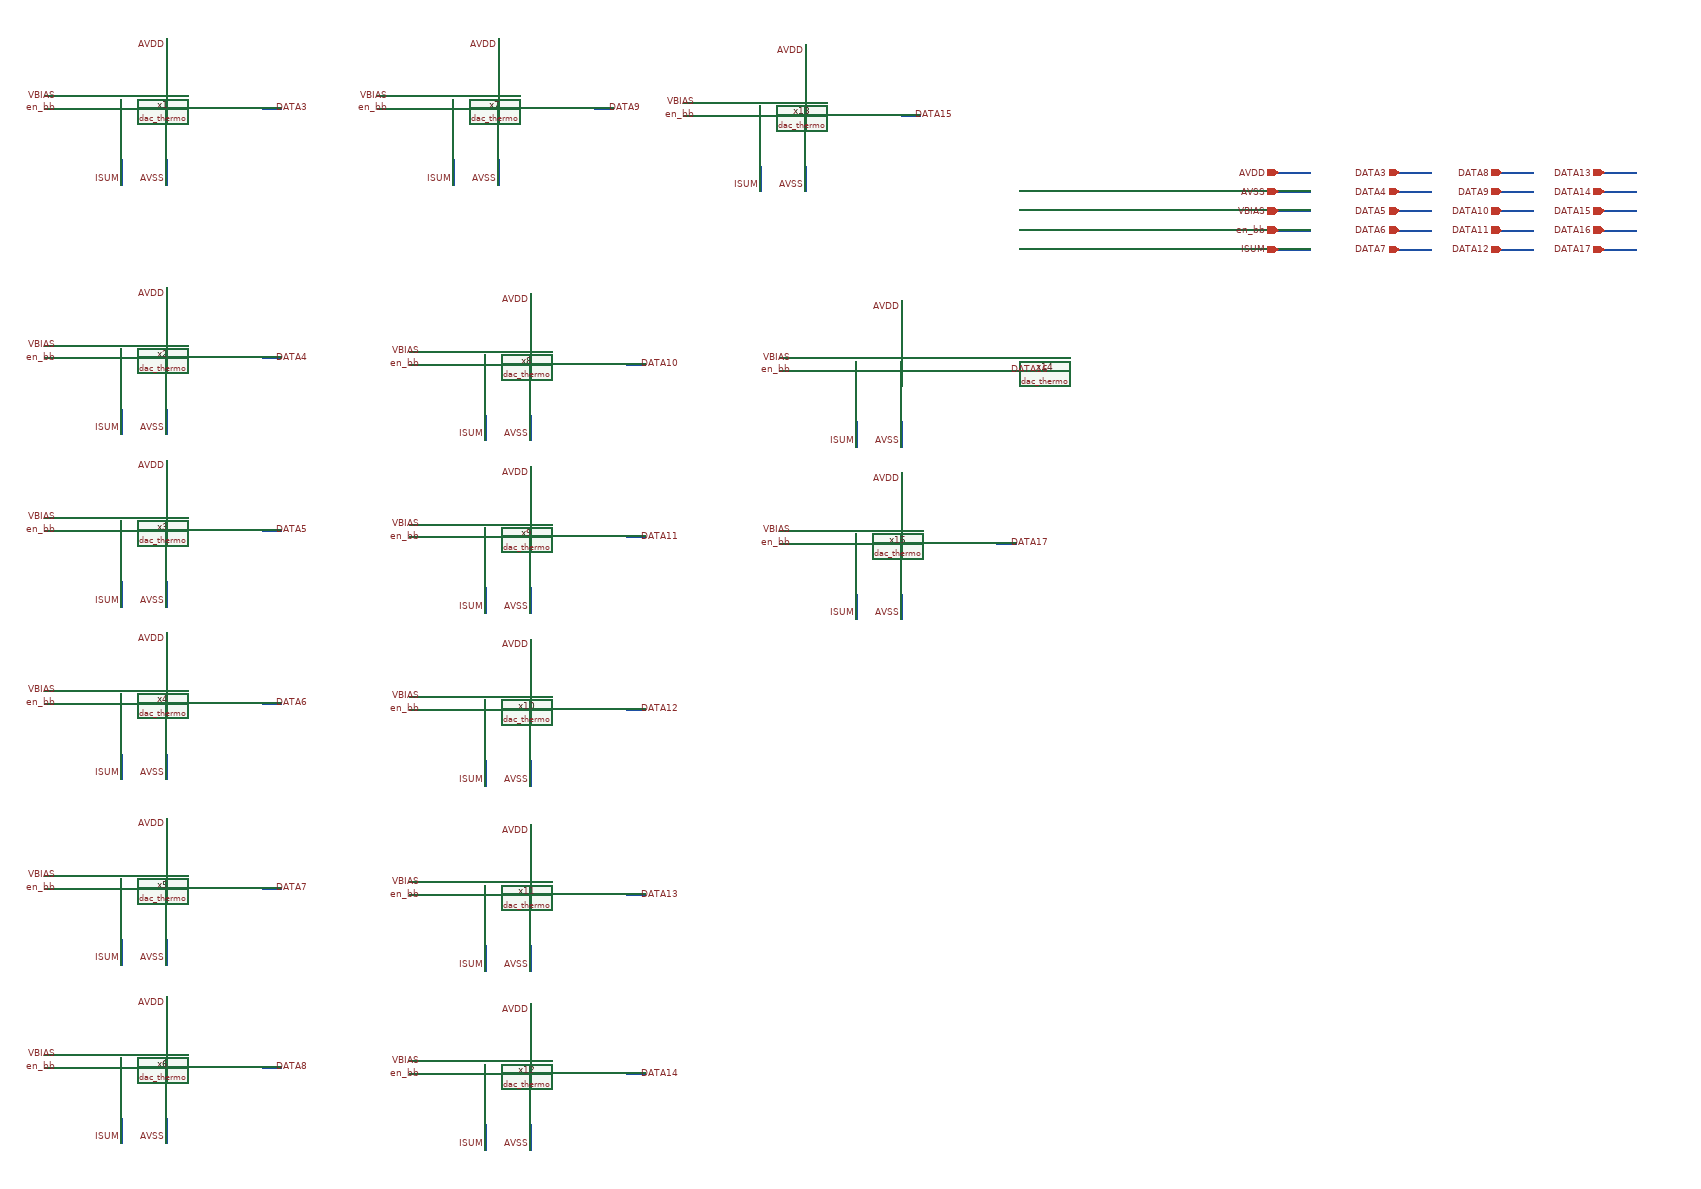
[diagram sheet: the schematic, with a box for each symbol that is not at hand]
v {xschem version=3.4.8RC file_version=1.3}
G {}
K {}
V {}
S {}
F {}
E {}
N 240 -1890 240 -1860 {lab=AVDD}
N 240 -1700 240 -1660 {lab=AVSS}
N 170 -1700 170 -1660 {lab=ISUM}
N 50 -1780 90 -1780 {lab=en_bb}
N 50 -1800 90 -1800 {lab=VBIAS}
N 390 -1780 420 -1780 {lab=DATA3}
N 240 -1500 240 -1470 {lab=AVDD}
N 240 -1310 240 -1270 {lab=AVSS}
N 170 -1310 170 -1270 {lab=ISUM}
N 50 -1390 90 -1390 {lab=en_bb}
N 50 -1410 90 -1410 {lab=VBIAS}
N 390 -1390 420 -1390 {lab=DATA4}
N 240 -1230 240 -1200 {lab=AVDD}
N 240 -1040 240 -1000 {lab=AVSS}
N 170 -1040 170 -1000 {lab=ISUM}
N 50 -1120 90 -1120 {lab=en_bb}
N 50 -1140 90 -1140 {lab=VBIAS}
N 390 -1120 420 -1120 {lab=DATA5}
N 240 -960 240 -930 {lab=AVDD}
N 240 -770 240 -730 {lab=AVSS}
N 170 -770 170 -730 {lab=ISUM}
N 50 -850 90 -850 {lab=en_bb}
N 50 -870 90 -870 {lab=VBIAS}
N 390 -850 420 -850 {lab=DATA6}
N 240 -670 240 -640 {lab=AVDD}
N 240 -480 240 -440 {lab=AVSS}
N 170 -480 170 -440 {lab=ISUM}
N 50 -560 90 -560 {lab=en_bb}
N 50 -580 90 -580 {lab=VBIAS}
N 390 -560 420 -560 {lab=DATA7}
N 240 -390 240 -360 {lab=AVDD}
N 240 -200 240 -160 {lab=AVSS}
N 170 -200 170 -160 {lab=ISUM}
N 50 -280 90 -280 {lab=en_bb}
N 50 -300 90 -300 {lab=VBIAS}
N 390 -280 420 -280 {lab=DATA8}
N 760 -1890 760 -1860 {lab=AVDD}
N 760 -1700 760 -1660 {lab=AVSS}
N 690 -1700 690 -1660 {lab=ISUM}
N 570 -1780 610 -1780 {lab=en_bb}
N 570 -1800 610 -1800 {lab=VBIAS}
N 910 -1780 940 -1780 {lab=DATA9}
N 810 -1490 810 -1460 {lab=AVDD}
N 810 -1300 810 -1260 {lab=AVSS}
N 740 -1300 740 -1260 {lab=ISUM}
N 620 -1380 660 -1380 {lab=en_bb}
N 620 -1400 660 -1400 {lab=VBIAS}
N 960 -1380 990 -1380 {lab=DATA10}
N 810 -1220 810 -1190 {lab=AVDD}
N 810 -1030 810 -990 {lab=AVSS}
N 740 -1030 740 -990 {lab=ISUM}
N 620 -1110 660 -1110 {lab=en_bb}
N 620 -1130 660 -1130 {lab=VBIAS}
N 960 -1110 990 -1110 {lab=DATA11}
N 810 -950 810 -920 {lab=AVDD}
N 810 -760 810 -720 {lab=AVSS}
N 740 -760 740 -720 {lab=ISUM}
N 620 -840 660 -840 {lab=en_bb}
N 620 -860 660 -860 {lab=VBIAS}
N 960 -840 990 -840 {lab=DATA12}
N 810 -660 810 -630 {lab=AVDD}
N 810 -470 810 -430 {lab=AVSS}
N 740 -470 740 -430 {lab=ISUM}
N 620 -550 660 -550 {lab=en_bb}
N 620 -570 660 -570 {lab=VBIAS}
N 960 -550 990 -550 {lab=DATA13}
N 810 -380 810 -350 {lab=AVDD}
N 810 -190 810 -150 {lab=AVSS}
N 740 -190 740 -150 {lab=ISUM}
N 620 -270 660 -270 {lab=en_bb}
N 620 -290 660 -290 {lab=VBIAS}
N 960 -270 990 -270 {lab=DATA14}
N 1240 -1880 1240 -1850 {lab=AVDD}
N 1240 -1690 1240 -1650 {lab=AVSS}
N 1170 -1690 1170 -1650 {lab=ISUM}
N 1050 -1770 1090 -1770 {lab=en_bb}
N 1050 -1790 1090 -1790 {lab=VBIAS}
N 1390 -1770 1420 -1770 {lab=DATA15}
N 1390 -1480 1390 -1450 {lab=AVDD}
N 1390 -1290 1390 -1250 {lab=AVSS}
N 1320 -1290 1320 -1250 {lab=ISUM}
N 1200 -1370 1240 -1370 {lab=en_bb}
N 1200 -1390 1240 -1390 {lab=VBIAS}
N 1540 -1370 1570 -1370 {lab=DATA16}
N 1390 -1210 1390 -1180 {lab=AVDD}
N 1390 -1020 1390 -980 {lab=AVSS}
N 1320 -1020 1320 -980 {lab=ISUM}
N 1200 -1100 1240 -1100 {lab=en_bb}
N 1200 -1120 1240 -1120 {lab=VBIAS}
N 1540 -1100 1570 -1100 {lab=DATA17}
N 1980 -1680 2030 -1680 {lab=AVDD}
N 1980 -1650 2030 -1650 {lab=AVSS}
N 1980 -1620 2030 -1620 {lab=VBIAS}
N 2170 -1680 2220 -1680 {lab=DATA3}
N 1980 -1590 2030 -1590 {lab=en_bb}
N 1980 -1560 2030 -1560 {lab=ISUM}
N 2170 -1650 2220 -1650 {lab=DATA4}
N 2170 -1620 2220 -1620 {lab=DATA5}
N 2170 -1590 2220 -1590 {lab=DATA6}
N 2170 -1560 2220 -1560 {lab=DATA7}
N 2330 -1680 2380 -1680 {lab=DATA8}
N 2330 -1650 2380 -1650 {lab=DATA9}
N 2330 -1620 2380 -1620 {lab=DATA10}
N 2330 -1590 2380 -1590 {lab=DATA11}
N 2330 -1560 2380 -1560 {lab=DATA12}
N 2490 -1680 2540 -1680 {lab=DATA13}
N 2490 -1650 2540 -1650 {lab=DATA14}
N 2490 -1620 2540 -1620 {lab=DATA15}
N 2490 -1590 2540 -1590 {lab=DATA16}
N 2490 -1560 2540 -1560 {lab=DATA17}
C {dac_thermo.sym} 240 -1780 0 0 {name=x1}
C {lab_wire.sym} 240 -1880 0 0 {name=p15 sig_type=std_logic lab=AVDD}
C {lab_wire.sym} 240 -1670 0 0 {name=p1 sig_type=std_logic lab=AVSS}
C {lab_wire.sym} 170 -1670 0 0 {name=p32 sig_type=std_logic lab=ISUM}
C {lab_wire.sym} 70 -1800 0 0 {name=p20 sig_type=std_logic lab=VBIAS}
C {lab_wire.sym} 70 -1780 0 0 {name=p21 sig_type=std_logic lab=en_bb}
C {lab_wire.sym} 410 -1780 0 1 {name=p2 sig_type=std_logic lab=DATA3}
C {dac_thermo.sym} 240 -1390 0 0 {name=x2}
C {lab_wire.sym} 240 -1490 0 0 {name=p3 sig_type=std_logic lab=AVDD}
C {lab_wire.sym} 240 -1280 0 0 {name=p4 sig_type=std_logic lab=AVSS}
C {lab_wire.sym} 170 -1280 0 0 {name=p5 sig_type=std_logic lab=ISUM}
C {lab_wire.sym} 70 -1410 0 0 {name=p6 sig_type=std_logic lab=VBIAS}
C {lab_wire.sym} 70 -1390 0 0 {name=p7 sig_type=std_logic lab=en_bb}
C {lab_wire.sym} 410 -1390 0 1 {name=p8 sig_type=std_logic lab=DATA4}
C {dac_thermo.sym} 240 -1120 0 0 {name=x3}
C {lab_wire.sym} 240 -1220 0 0 {name=p9 sig_type=std_logic lab=AVDD}
C {lab_wire.sym} 240 -1010 0 0 {name=p10 sig_type=std_logic lab=AVSS}
C {lab_wire.sym} 170 -1010 0 0 {name=p11 sig_type=std_logic lab=ISUM}
C {lab_wire.sym} 70 -1140 0 0 {name=p12 sig_type=std_logic lab=VBIAS}
C {lab_wire.sym} 70 -1120 0 0 {name=p13 sig_type=std_logic lab=en_bb}
C {lab_wire.sym} 410 -1120 0 1 {name=p14 sig_type=std_logic lab=DATA5}
C {dac_thermo.sym} 240 -850 0 0 {name=x4}
C {lab_wire.sym} 240 -950 0 0 {name=p16 sig_type=std_logic lab=AVDD}
C {lab_wire.sym} 240 -740 0 0 {name=p17 sig_type=std_logic lab=AVSS}
C {lab_wire.sym} 170 -740 0 0 {name=p18 sig_type=std_logic lab=ISUM}
C {lab_wire.sym} 70 -870 0 0 {name=p19 sig_type=std_logic lab=VBIAS}
C {lab_wire.sym} 70 -850 0 0 {name=p22 sig_type=std_logic lab=en_bb}
C {lab_wire.sym} 410 -850 0 1 {name=p23 sig_type=std_logic lab=DATA6}
C {dac_thermo.sym} 240 -560 0 0 {name=x5}
C {lab_wire.sym} 240 -660 0 0 {name=p24 sig_type=std_logic lab=AVDD}
C {lab_wire.sym} 240 -450 0 0 {name=p25 sig_type=std_logic lab=AVSS}
C {lab_wire.sym} 170 -450 0 0 {name=p26 sig_type=std_logic lab=ISUM}
C {lab_wire.sym} 70 -580 0 0 {name=p27 sig_type=std_logic lab=VBIAS}
C {lab_wire.sym} 70 -560 0 0 {name=p28 sig_type=std_logic lab=en_bb}
C {lab_wire.sym} 410 -560 0 1 {name=p29 sig_type=std_logic lab=DATA7}
C {dac_thermo.sym} 240 -280 0 0 {name=x6}
C {lab_wire.sym} 240 -380 0 0 {name=p30 sig_type=std_logic lab=AVDD}
C {lab_wire.sym} 240 -170 0 0 {name=p31 sig_type=std_logic lab=AVSS}
C {lab_wire.sym} 170 -170 0 0 {name=p33 sig_type=std_logic lab=ISUM}
C {lab_wire.sym} 70 -300 0 0 {name=p34 sig_type=std_logic lab=VBIAS}
C {lab_wire.sym} 70 -280 0 0 {name=p35 sig_type=std_logic lab=en_bb}
C {lab_wire.sym} 410 -280 0 1 {name=p36 sig_type=std_logic lab=DATA8}
C {dac_thermo.sym} 760 -1780 0 0 {name=x7}
C {lab_wire.sym} 760 -1880 0 0 {name=p37 sig_type=std_logic lab=AVDD}
C {lab_wire.sym} 760 -1670 0 0 {name=p38 sig_type=std_logic lab=AVSS}
C {lab_wire.sym} 690 -1670 0 0 {name=p39 sig_type=std_logic lab=ISUM}
C {lab_wire.sym} 590 -1800 0 0 {name=p40 sig_type=std_logic lab=VBIAS}
C {lab_wire.sym} 590 -1780 0 0 {name=p41 sig_type=std_logic lab=en_bb}
C {lab_wire.sym} 930 -1780 0 1 {name=p42 sig_type=std_logic lab=DATA9}
C {dac_thermo.sym} 810 -1380 0 0 {name=x8}
C {lab_wire.sym} 810 -1480 0 0 {name=p43 sig_type=std_logic lab=AVDD}
C {lab_wire.sym} 810 -1270 0 0 {name=p44 sig_type=std_logic lab=AVSS}
C {lab_wire.sym} 740 -1270 0 0 {name=p45 sig_type=std_logic lab=ISUM}
C {lab_wire.sym} 640 -1400 0 0 {name=p46 sig_type=std_logic lab=VBIAS}
C {lab_wire.sym} 640 -1380 0 0 {name=p47 sig_type=std_logic lab=en_bb}
C {lab_wire.sym} 980 -1380 0 1 {name=p48 sig_type=std_logic lab=DATA10}
C {dac_thermo.sym} 810 -1110 0 0 {name=x9}
C {lab_wire.sym} 810 -1210 0 0 {name=p49 sig_type=std_logic lab=AVDD}
C {lab_wire.sym} 810 -1000 0 0 {name=p50 sig_type=std_logic lab=AVSS}
C {lab_wire.sym} 740 -1000 0 0 {name=p51 sig_type=std_logic lab=ISUM}
C {lab_wire.sym} 640 -1130 0 0 {name=p52 sig_type=std_logic lab=VBIAS}
C {lab_wire.sym} 640 -1110 0 0 {name=p53 sig_type=std_logic lab=en_bb}
C {lab_wire.sym} 980 -1110 0 1 {name=p54 sig_type=std_logic lab=DATA11}
C {dac_thermo.sym} 810 -840 0 0 {name=x10}
C {lab_wire.sym} 810 -940 0 0 {name=p55 sig_type=std_logic lab=AVDD}
C {lab_wire.sym} 810 -730 0 0 {name=p56 sig_type=std_logic lab=AVSS}
C {lab_wire.sym} 740 -730 0 0 {name=p57 sig_type=std_logic lab=ISUM}
C {lab_wire.sym} 640 -860 0 0 {name=p58 sig_type=std_logic lab=VBIAS}
C {lab_wire.sym} 640 -840 0 0 {name=p59 sig_type=std_logic lab=en_bb}
C {lab_wire.sym} 980 -840 0 1 {name=p60 sig_type=std_logic lab=DATA12}
C {dac_thermo.sym} 810 -550 0 0 {name=x11}
C {lab_wire.sym} 810 -650 0 0 {name=p61 sig_type=std_logic lab=AVDD}
C {lab_wire.sym} 810 -440 0 0 {name=p62 sig_type=std_logic lab=AVSS}
C {lab_wire.sym} 740 -440 0 0 {name=p63 sig_type=std_logic lab=ISUM}
C {lab_wire.sym} 640 -570 0 0 {name=p64 sig_type=std_logic lab=VBIAS}
C {lab_wire.sym} 640 -550 0 0 {name=p65 sig_type=std_logic lab=en_bb}
C {lab_wire.sym} 980 -550 0 1 {name=p66 sig_type=std_logic lab=DATA13}
C {dac_thermo.sym} 810 -270 0 0 {name=x12}
C {lab_wire.sym} 810 -370 0 0 {name=p67 sig_type=std_logic lab=AVDD}
C {lab_wire.sym} 810 -160 0 0 {name=p68 sig_type=std_logic lab=AVSS}
C {lab_wire.sym} 740 -160 0 0 {name=p69 sig_type=std_logic lab=ISUM}
C {lab_wire.sym} 640 -290 0 0 {name=p70 sig_type=std_logic lab=VBIAS}
C {lab_wire.sym} 640 -270 0 0 {name=p71 sig_type=std_logic lab=en_bb}
C {lab_wire.sym} 980 -270 0 1 {name=p72 sig_type=std_logic lab=DATA14}
C {dac_thermo.sym} 1240 -1770 0 0 {name=x13}
C {lab_wire.sym} 1240 -1870 0 0 {name=p73 sig_type=std_logic lab=AVDD}
C {lab_wire.sym} 1240 -1660 0 0 {name=p74 sig_type=std_logic lab=AVSS}
C {lab_wire.sym} 1170 -1660 0 0 {name=p75 sig_type=std_logic lab=ISUM}
C {lab_wire.sym} 1070 -1790 0 0 {name=p76 sig_type=std_logic lab=VBIAS}
C {lab_wire.sym} 1070 -1770 0 0 {name=p77 sig_type=std_logic lab=en_bb}
C {lab_wire.sym} 1410 -1770 0 1 {name=p78 sig_type=std_logic lab=DATA15}
C {dac_thermo.sym} 1390 -1370 0 0 {name=x14}
C {lab_wire.sym} 1390 -1470 0 0 {name=p79 sig_type=std_logic lab=AVDD}
C {lab_wire.sym} 1390 -1260 0 0 {name=p80 sig_type=std_logic lab=AVSS}
C {lab_wire.sym} 1320 -1260 0 0 {name=p81 sig_type=std_logic lab=ISUM}
C {lab_wire.sym} 1220 -1390 0 0 {name=p82 sig_type=std_logic lab=VBIAS}
C {lab_wire.sym} 1220 -1370 0 0 {name=p83 sig_type=std_logic lab=en_bb}
C {lab_wire.sym} 1560 -1370 0 1 {name=p84 sig_type=std_logic lab=DATA16}
C {dac_thermo.sym} 1390 -1100 0 0 {name=x15}
C {lab_wire.sym} 1390 -1200 0 0 {name=p85 sig_type=std_logic lab=AVDD}
C {lab_wire.sym} 1390 -990 0 0 {name=p86 sig_type=std_logic lab=AVSS}
C {lab_wire.sym} 1320 -990 0 0 {name=p87 sig_type=std_logic lab=ISUM}
C {lab_wire.sym} 1220 -1120 0 0 {name=p88 sig_type=std_logic lab=VBIAS}
C {lab_wire.sym} 1220 -1100 0 0 {name=p89 sig_type=std_logic lab=en_bb}
C {lab_wire.sym} 1560 -1100 0 1 {name=p90 sig_type=std_logic lab=DATA17}
C {iopin.sym} 1980 -1680 2 0 {name=p91 lab=AVDD}
C {iopin.sym} 1980 -1650 2 0 {name=p92 lab=AVSS}
C {iopin.sym} 1980 -1620 2 0 {name=p93 lab=VBIAS}
C {iopin.sym} 1980 -1590 2 0 {name=p94 lab=en_bb}
C {iopin.sym} 2170 -1650 2 0 {name=p95 lab=DATA4}
C {iopin.sym} 1980 -1560 2 0 {name=p96 lab=ISUM}
C {iopin.sym} 2170 -1680 2 0 {name=p97 lab=DATA3}
C {iopin.sym} 2170 -1620 2 0 {name=p98 lab=DATA5}
C {iopin.sym} 2170 -1560 2 0 {name=p99 lab=DATA7}
C {iopin.sym} 2170 -1590 2 0 {name=p100 lab=DATA6}
C {iopin.sym} 2330 -1680 2 0 {name=p101 lab=DATA8}
C {iopin.sym} 2330 -1650 2 0 {name=p102 lab=DATA9}
C {iopin.sym} 2330 -1620 2 0 {name=p103 lab=DATA10}
C {iopin.sym} 2330 -1560 2 0 {name=p104 lab=DATA12}
C {iopin.sym} 2330 -1590 2 0 {name=p105 lab=DATA11}
C {iopin.sym} 2490 -1680 2 0 {name=p106 lab=DATA13}
C {iopin.sym} 2490 -1650 2 0 {name=p107 lab=DATA14}
C {iopin.sym} 2490 -1620 2 0 {name=p108 lab=DATA15}
C {iopin.sym} 2490 -1590 2 0 {name=p109 lab=DATA16}
C {iopin.sym} 2490 -1560 2 0 {name=p110 lab=DATA17}
